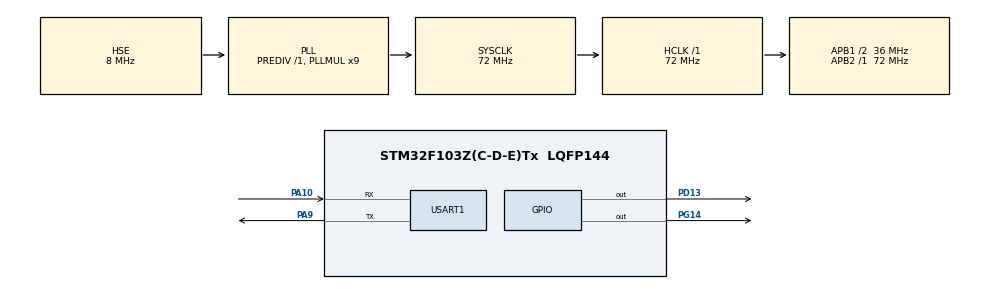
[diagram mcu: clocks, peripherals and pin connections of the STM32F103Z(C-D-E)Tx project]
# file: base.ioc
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Mcu.Family=STM32F1
Mcu.Name=STM32F103Z(C-D-E)Tx
Mcu.Package=LQFP144
NVIC.PriorityGroup=NVIC_PRIORITYGROUP_4
OSC_IN.Mode=HSE-External-Oscillator
OSC_IN.Signal=RCC_OSC_IN
OSC_OUT.Mode=HSE-External-Oscillator
OSC_OUT.Signal=RCC_OSC_OUT
PA10.Mode=Asynchronous
PA10.Signal=USART1_RX
PA9.Mode=Asynchronous
PA9.Signal=USART1_TX
PD13.Signal=GPIO_Output
PG14.Signal=GPIO_Output
ProjectManager.HeapSize=0x200
ProjectManager.StackSize=0x400
ProjectManager.TargetToolchain=CMake
RCC.AHBFreq_Value=72000000
RCC.APB1CLKDivider=RCC_HCLK_DIV2
RCC.APB1Freq_Value=36000000
RCC.APB1TimFreq_Value=72000000
RCC.APB2Freq_Value=72000000
RCC.APB2TimFreq_Value=72000000
RCC.HCLKFreq_Value=72000000
RCC.PLLMUL=RCC_PLL_MUL9
RCC.PLLSourceVirtual=RCC_PLLSOURCE_HSE
RCC.SYSCLKFreq_VALUE=72000000
RCC.SYSCLKSource=RCC_SYSCLKSOURCE_PLLCLK
RCC.USBFreq_Value=72000000
USART1.VirtualMode=VM_ASYNC
VP_SYS_VS_ND.Mode=No_Debug
board=custom

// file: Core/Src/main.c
/* USER CODE BEGIN Header */
/**
  ******************************************************************************
  * @file           : main.c
  * @brief          : Main program body
  ******************************************************************************
  * @attention
  *
  * Copyright (c) 2025 STMicroelectronics.
  * All rights reserved.
  *
  * This software is licensed under terms that can be found in the LICENSE file
  * in the root directory of this software component.
  * If no LICENSE file comes with this software, it is provided AS-IS.
  *
  ******************************************************************************
  */
/* USER CODE END Header */
#include <stdint.h>
#include "stm32f1xx_hal.h"
#include "main.h"
#include <stdio.h>

UART_HandleTypeDef huart1;

void SystemClock_Config(void);
static void MX_GPIO_Init(void);
static void MX_USART1_UART_Init(void);

/* USER CODE BEGIN 0 */
// printf重定向到UART1
#if 0
#not work
int fputc(int ch, FILE *f)
{
    HAL_UART_Transmit(&huart1, (uint8_t *)&ch, 1, 0xFFFF);
    return ch;
}
#endif

#ifdef __GNUC__

int _write(int fd, char *ptr, int len)
{
  HAL_UART_Transmit(&huart1, (uint8_t*)ptr, len, 0xFFFF);
  return len;
}
#endif

/* USER CODE END 0 */

int main(void)
{

  /* MCU Configuration--------------------------------------------------------*/

  /* Reset of all peripherals, Initializes the Flash interface and the Systick. */
  HAL_Init();

  /* Configure the system clock */
  SystemClock_Config();

  /* Initialize all configured peripherals */
  MX_GPIO_Init();
  MX_USART1_UART_Init();

  /* Infinite loop */
  while (1)
  {

    /* USER CODE BEGIN 3 */
    HAL_GPIO_TogglePin(GPIOB, GPIO_PIN_5);
    HAL_GPIO_TogglePin(GPIOE, GPIO_PIN_5);
    printf("hello2\r\n");
    HAL_UART_Transmit(&huart1, (uint8_t *)"hello\r\n", 7, 0xFFFF);
    HAL_Delay(500);
  }
  /* USER CODE END 3 */
}

void SystemClock_Config(void)
{
  RCC_OscInitTypeDef RCC_OscInitStruct = {0};
  RCC_ClkInitTypeDef RCC_ClkInitStruct = {0};

  /** Initializes the RCC Oscillators according to the specified parameters
  * in the RCC_OscInitTypeDef structure.
  */
  RCC_OscInitStruct.OscillatorType = RCC_OSCILLATORTYPE_HSE;
  RCC_OscInitStruct.HSEState = RCC_HSE_ON;
  RCC_OscInitStruct.HSEPredivValue = RCC_HSE_PREDIV_DIV1;
  RCC_OscInitStruct.HSIState = RCC_HSI_ON;
  RCC_OscInitStruct.PLL.PLLState = RCC_PLL_ON;
  RCC_OscInitStruct.PLL.PLLSource = RCC_PLLSOURCE_HSE;
  RCC_OscInitStruct.PLL.PLLMUL = RCC_PLL_MUL9;
  if (HAL_RCC_OscConfig(&RCC_OscInitStruct) != HAL_OK)
  {
    Error_Handler();
  }

  /** Initializes the CPU, AHB and APB buses clocks
  */
  RCC_ClkInitStruct.ClockType = RCC_CLOCKTYPE_HCLK|RCC_CLOCKTYPE_SYSCLK
                              |RCC_CLOCKTYPE_PCLK1|RCC_CLOCKTYPE_PCLK2;
  RCC_ClkInitStruct.SYSCLKSource = RCC_SYSCLKSOURCE_PLLCLK;
  RCC_ClkInitStruct.AHBCLKDivider = RCC_SYSCLK_DIV1;
  RCC_ClkInitStruct.APB1CLKDivider = RCC_HCLK_DIV2;
  RCC_ClkInitStruct.APB2CLKDivider = RCC_HCLK_DIV1;

  if (HAL_RCC_ClockConfig(&RCC_ClkInitStruct, FLASH_LATENCY_2) != HAL_OK)
  {
    Error_Handler();
  }
}

static void MX_USART1_UART_Init(void)
{

  huart1.Instance = USART1;
  huart1.Init.BaudRate = 115200;
  huart1.Init.WordLength = UART_WORDLENGTH_8B;
  huart1.Init.StopBits = UART_STOPBITS_1;
  huart1.Init.Parity = UART_PARITY_NONE;
  huart1.Init.Mode = UART_MODE_TX_RX;
  huart1.Init.HwFlowCtl = UART_HWCONTROL_NONE;
  huart1.Init.OverSampling = UART_OVERSAMPLING_16;
  if (HAL_UART_Init(&huart1) != HAL_OK)
  {
    Error_Handler();
  }

}

static void MX_GPIO_Init(void)
{
  GPIO_InitTypeDef GPIO_InitStruct = {0};

  /* GPIO Ports Clock Enable */
  __HAL_RCC_GPIOD_CLK_ENABLE();
  __HAL_RCC_GPIOA_CLK_ENABLE();
  __HAL_RCC_GPIOG_CLK_ENABLE();
  __HAL_RCC_GPIOB_CLK_ENABLE();
  __HAL_RCC_GPIOE_CLK_ENABLE();

  /*Configure GPIO pin Output Level */
  HAL_GPIO_WritePin(GPIOD, GPIO_PIN_13, GPIO_PIN_RESET);
  HAL_GPIO_WritePin(GPIOG, GPIO_PIN_14, GPIO_PIN_RESET);
  HAL_GPIO_WritePin(GPIOB, GPIO_PIN_5, GPIO_PIN_RESET);
  HAL_GPIO_WritePin(GPIOE, GPIO_PIN_5, GPIO_PIN_RESET);

  /*Configure GPIO pin : PD13 */
  GPIO_InitStruct.Pin = GPIO_PIN_13;
  GPIO_InitStruct.Mode = GPIO_MODE_OUTPUT_PP;
  GPIO_InitStruct.Pull = GPIO_NOPULL;
  GPIO_InitStruct.Speed = GPIO_SPEED_FREQ_LOW;
  HAL_GPIO_Init(GPIOD, &GPIO_InitStruct);

  /*Configure GPIO pin : PG14 */
  GPIO_InitStruct.Pin = GPIO_PIN_14;
  GPIO_InitStruct.Mode = GPIO_MODE_OUTPUT_PP;
  GPIO_InitStruct.Pull = GPIO_NOPULL;
  GPIO_InitStruct.Speed = GPIO_SPEED_FREQ_LOW;
  HAL_GPIO_Init(GPIOG, &GPIO_InitStruct);

  /*Configure GPIO pin : PB5 */
  GPIO_InitStruct.Pin = GPIO_PIN_5;
  GPIO_InitStruct.Mode = GPIO_MODE_OUTPUT_PP;
  GPIO_InitStruct.Pull = GPIO_NOPULL;
  GPIO_InitStruct.Speed = GPIO_SPEED_FREQ_LOW;
  HAL_GPIO_Init(GPIOB, &GPIO_InitStruct);

  /*Configure GPIO pin : PE5 */
  GPIO_InitStruct.Pin = GPIO_PIN_5;
  GPIO_InitStruct.Mode = GPIO_MODE_OUTPUT_PP;
  GPIO_InitStruct.Pull = GPIO_NOPULL;
  GPIO_InitStruct.Speed = GPIO_SPEED_FREQ_LOW;
  HAL_GPIO_Init(GPIOE, &GPIO_InitStruct);

  /*Configure GPIO pin : PA9 (UART1 TX) */
  GPIO_InitStruct.Pin = GPIO_PIN_9;
  GPIO_InitStruct.Mode = GPIO_MODE_AF_PP;
  GPIO_InitStruct.Pull = GPIO_NOPULL;
  GPIO_InitStruct.Speed = GPIO_SPEED_FREQ_HIGH;
  HAL_GPIO_Init(GPIOA, &GPIO_InitStruct);

  /*Configure GPIO pin : PA10 (UART1 RX) */
  GPIO_InitStruct.Pin = GPIO_PIN_10;
  GPIO_InitStruct.Mode = GPIO_MODE_AF_INPUT;
  GPIO_InitStruct.Pull = GPIO_NOPULL;
  HAL_GPIO_Init(GPIOA, &GPIO_InitStruct);

}

void Error_Handler(void)
{
  __disable_irq();
  while (1)
  {
  }
}
